VERSION 5.7 ;
  NOWIREEXTENSIONATPIN ON ;
  DIVIDERCHAR "/" ;
  BUSBITCHARS "[]" ;
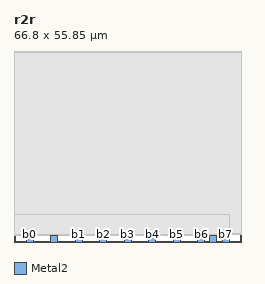
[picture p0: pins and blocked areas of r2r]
MACRO r2r
  CLASS BLOCK ;
  FOREIGN r2r ;
  ORIGIN 0.000 0.000 ;
  SIZE 66.800 BY 55.850 ;
  PIN b0
    PORT
      LAYER Metal2 ;
        RECT 3.600 0.000 5.600 1.800 ;
    END
  END b0
  PIN VGND
    ANTENNADIFFAREA 85.780800 ;
    PORT
      LAYER Metal2 ;
        RECT 10.800 0.000 12.800 1.800 ;
    END
  END VGND
  PIN b1
    PORT
      LAYER Metal2 ;
        RECT 18.000 0.000 20.000 1.800 ;
    END
  END b1
  PIN b2
    PORT
      LAYER Metal2 ;
        RECT 25.200 0.000 27.200 1.800 ;
    END
  END b2
  PIN b3
    PORT
      LAYER Metal2 ;
        RECT 32.400 0.000 34.400 1.800 ;
    END
  END b3
  PIN b4
    PORT
      LAYER Metal2 ;
        RECT 39.600 0.000 41.600 1.800 ;
    END
  END b4
  PIN b5
    PORT
      LAYER Metal2 ;
        RECT 46.800 0.000 48.800 1.800 ;
    END
  END b5
  PIN b6
    PORT
      LAYER Metal2 ;
        RECT 54.000 0.000 56.000 1.800 ;
    END
  END b6
  PIN b7
    PORT
      LAYER Metal2 ;
        RECT 61.200 0.000 63.200 1.800 ;
    END
  END b7
  PIN out
    PORT
      LAYER Metal2 ;
        RECT 57.600 0.000 59.600 1.800 ;
    END
  END out
  OBS
      LAYER Pwell ;
        RECT 0.000 2.300 66.760 55.880 ;
      LAYER Metal1 ;
        RECT 0.000 2.485 66.800 55.695 ;
      LAYER Metal2 ;
        RECT 0.000 2.100 63.200 8.200 ;
        RECT 0.000 1.800 3.300 2.100 ;
        RECT 5.900 1.800 10.500 2.100 ;
        RECT 13.100 1.800 17.700 2.100 ;
        RECT 20.300 1.800 24.900 2.100 ;
        RECT 27.500 1.800 32.100 2.100 ;
        RECT 34.700 1.800 39.300 2.100 ;
        RECT 41.900 1.800 46.500 2.100 ;
        RECT 49.100 1.800 53.700 2.100 ;
        RECT 56.300 1.800 57.300 2.100 ;
        RECT 59.900 1.800 60.900 2.100 ;
  END
END r2r
END LIBRARY

